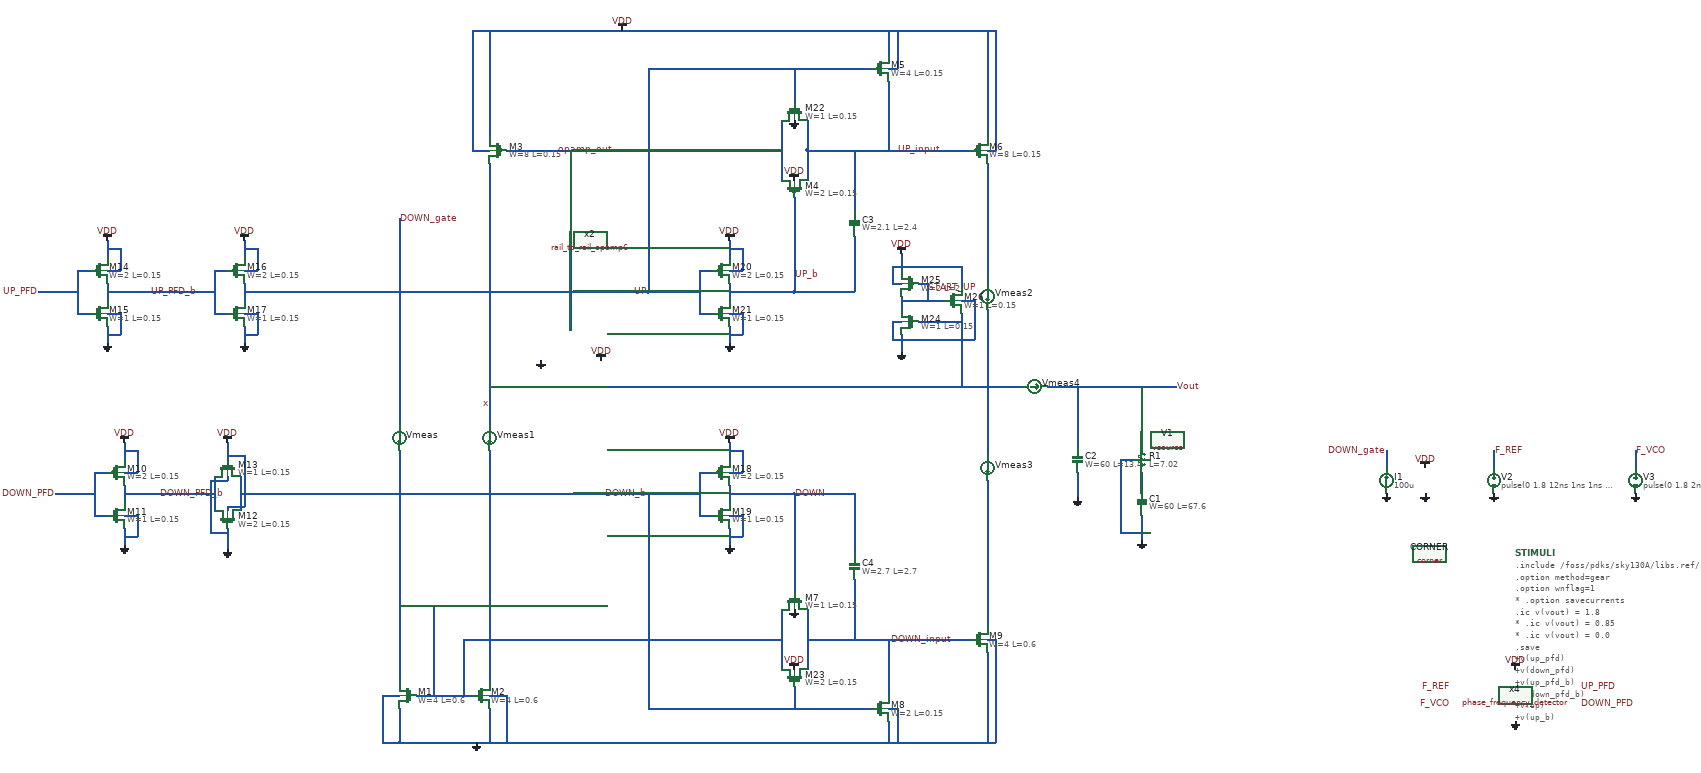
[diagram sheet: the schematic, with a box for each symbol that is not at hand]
v {xschem version=3.4.6 file_version=1.2}
G {}
K {}
V {}
S {}
E {}
B 2 1100 -2730 2140 -2250 {flags=graph
y1=-9.5e-05
y2=0.00017
ypos1=0
ypos2=2
divy=5
subdivy=1
unity=1
x1=-2.5e-08
x2=4.75e-07
divx=5
subdivx=1
xlabmag=1.0
ylabmag=1.0


dataset=0
unitx=1
logx=0
logy=0








linewidth_mult=4
color=6
node="\\"i(@m.xm6.msky130_fd_pr__pfet_01v8[id]) i(@m.xm9.msky130_fd_pr__nfet_01v8[id]) - \\""}
B 2 4200 -3800 5560 -3140 {flags=graph
y1=0
y2=1.8
ypos1=0
ypos2=2
divy=5
subdivy=1
unity=1
x1=-2.5e-08
x2=4.75e-07
divx=5
subdivx=1
xlabmag=1.0
ylabmag=1.0


dataset=0
unitx=1
logx=0
logy=0








linewidth_mult=3







autoload=0
sim_type=tran
color="6 7"
node="f_ref
f_vco"}
B 2 4200 -2410 5580 -1730 {flags=graph
y1=-0.02
y2=1.9
ypos1=0
ypos2=2
divy=5
subdivy=1
unity=1
x1=-2.5e-08
x2=4.75e-07
divx=5
subdivx=1
xlabmag=1.0
ylabmag=1.0


dataset=0
unitx=1
logx=0
logy=0








linewidth_mult=5





color="6 5"
node="up_pfd_b
down_pfd_b"}
B 2 4200 -3120 5580 -2420 {flags=graph
y1=-0.038
y2=1.9
ypos1=0
ypos2=2
divy=5
subdivy=1
unity=1
x1=-2.5e-08
x2=4.75e-07
divx=5
subdivx=1
xlabmag=1.0
ylabmag=1.0


dataset=0
unitx=1
logx=0
logy=0








linewidth_mult=5

color="6 5"
node="up_pfd
down_pfd"}
B 2 2220 -2740 3580 -2070 {flags=graph
y1=0.029
y2=1.9
ypos1=0
ypos2=2
divy=5
subdivy=1
unity=1
x1=-2.5e-08
x2=4.75e-07
divx=5
subdivx=1
xlabmag=1.0
ylabmag=1.0


dataset=0
unitx=1
logx=0
logy=0








linewidth_mult=3



color="9 7 6"
node="vout
x
opamp_out"}
B 2 200 -3250 960 -2910 {flags=graph
y1=-4.8e-06
y2=2
ypos1=0
ypos2=2
divy=5
subdivy=1
unity=1
x1=-2.5e-08
x2=4.75e-07
divx=5
subdivx=1
xlabmag=1.0
ylabmag=1.0


dataset=0
unitx=1
logx=0
logy=0








linewidth_mult=3



color="18 6 11 5 12"
node="opamp_out
up_input


down_gate
down_input


x"}
B 2 1100 -3240 2140 -2750 {flags=graph
y1=-8.2e-05
y2=0.00019
ypos1=0
ypos2=2
divy=5
subdivy=1
unity=1
x1=-2.5e-08
x2=4.75e-07
divx=5
subdivx=1
xlabmag=1.0
ylabmag=1.0


dataset=0
unitx=1
logx=0
logy=0








linewidth_mult=4




color="6 7"
node="i(vmeas2)
i(vmeas3)"}
B 2 2220 -2040 3580 -1370 {flags=graph
y1=0.14
y2=1.9
ypos1=0
ypos2=2
divy=5
subdivy=1
unity=1
x1=-2.5e-08
x2=4.75e-07
divx=5
subdivx=1
xlabmag=1.0
ylabmag=1.0


dataset=0
unitx=1
logx=0
logy=0








linewidth_mult=5



color=6
node=vout}
B 2 4200 -1710 5580 -1030 {flags=graph
y1=-0.013
y2=1.9
ypos1=0
ypos2=2
divy=5
subdivy=1
unity=1
x1=-2.5e-08
x2=4.75e-07
divx=5
subdivx=1
xlabmag=1.0
ylabmag=1.0


dataset=0
unitx=1
logx=0
logy=0








linewidth_mult=5





color="6 5"
node="up
down_b"}
B 2 4200 -1010 5580 -330 {flags=graph
y1=-0.04
y2=1.9
ypos1=0
ypos2=2
divy=5
subdivy=1
unity=1
x1=-2.5e-08
x2=4.75e-07
divx=5
subdivx=1
xlabmag=1.0
ylabmag=1.0


dataset=0
unitx=1
logx=0
logy=0








linewidth_mult=5





color="6 5"
node="up_b
down"}
B 2 40 -2730 1080 -2250 {flags=graph
y1=-9.5e-05
y2=0.00015
ypos1=0
ypos2=2
divy=5
subdivy=1
unity=1
x1=-2.5e-08
x2=4.75e-07
divx=5
subdivx=1
xlabmag=1.0
ylabmag=1.0


dataset=0
unitx=1
logx=0
logy=0








linewidth_mult=2

color="6 7 18"
node="i(vmeas1)
i(vmeas2)
i(vmeas4)"}
N 800 -570 930 -570 {
lab=#net1}
N 760 -540 760 -460 {
lab=GND}
N 760 -460 1260 -460 {
lab=GND}
N 720 -570 760 -570 {
lab=GND}
N 720 -570 720 -460 {
lab=GND}
N 720 -460 760 -460 {
lab=GND}
N 970 -570 1010 -570 {
lab=GND}
N 930 -1840 970 -1840 {
lab=VDD}
N 1260 -460 1300 -460 {
lab=GND}
N 970 -2120 970 -1870 {
lab=VDD}
N 930 -2120 930 -1840 {
lab=VDD}
N 2130 -2120 2130 -1870 {
lab=VDD}
N 1900 -2120 1900 -2060 {
lab=VDD}
N 1900 -2030 1920 -2030 {
lab=VDD}
N 1920 -2120 1920 -2030 {
lab=VDD}
N 2150 -2120 2150 -1840 {
lab=VDD}
N 2130 -1840 2150 -1840 {
lab=VDD}
N 2130 -1810 2130 -1530 {
lab=#net2}
N 1300 -460 1900 -460 {
lab=GND}
N 1900 -510 1900 -460 {
lab=GND}
N 2130 -700 2150 -700 {
lab=GND}
N 2130 -460 2150 -460 {
lab=GND}
N 180 -1510 280 -1510 {
lab=UP_PFD_b}
N 220 -1040 330 -1040 {
lab=DOWN_PFD_b}
N -80 -1510 -40 -1510 {
lab=UP_PFD}
N -40 -1040 0 -1040 {
lab=DOWN_PFD}
N 970 -1810 970 -1410 {
lab=x}
N 970 -1290 1140 -1290 {
lab=x}
N 1180 -1290 2130 -1290 {
lab=#net3}
N 2490 -1090 2490 -1040 {
lab=#net4}
N 2490 -1290 2490 -1150 {
lab=Vout}
N 2490 -990 2490 -930 {
lab=GND}
N 2440 -1120 2470 -1120 {
lab=GND}
N 2440 -1120 2440 -950 {
lab=GND}
N 2440 -950 2490 -950 {
lab=GND}
N 2340 -1290 2340 -1150 {
lab=Vout}
N 2340 -1090 2340 -1030 {
lab=GND}
N 3310 -1140 3310 -1100 {
lab=F_REF}
N 3640 -1140 3640 -1100 {
lab=F_VCO}
N 2270 -1290 2570 -1290 {
lab=Vout}
N 840 -780 840 -570 {
lab=#net1}
N 760 -780 840 -780 {
lab=#net1}
N 1010 -570 1010 -460 {
lab=GND}
N 970 -540 970 -460 {
lab=GND}
N 910 -700 1650 -700 {
lab=#net1}
N 390 -1040 1410 -1040 {
lab=DOWN_b}
N 1680 -1730 1680 -1510 {
lab=UP_b}
N 1340 -2030 1860 -2030 {
lab=UP}
N 1340 -2030 1340 -1510 {
lab=UP}
N 1900 -2000 1900 -1840 {
lab=UP_input}
N 1710 -1840 2090 -1840 {
lab=UP_input}
N 930 -2120 2150 -2120 {
lab=VDD}
N 1620 -1040 1680 -1040 {
lab=DOWN}
N 1680 -1040 1680 -810 {
lab=DOWN}
N 1340 -1040 1340 -540 {
lab=DOWN_b}
N 1340 -540 1860 -540 {
lab=DOWN_b}
N 330 -1080 330 -1000 {
lab=DOWN_PFD_b}
N 390 -1080 390 -1000 {
lab=DOWN_b}
N 360 -1160 360 -1120 {
lab=VDD}
N 360 -1010 360 -1000 {
lab=VDD}
N 360 -1010 400 -1010 {
lab=VDD}
N 400 -1130 400 -1010 {
lab=VDD}
N 360 -1130 400 -1130 {
lab=VDD}
N 360 -1080 360 -1070 {
lab=GND}
N 320 -1070 360 -1070 {
lab=GND}
N 320 -1070 320 -950 {
lab=GND}
N 320 -950 360 -950 {
lab=GND}
N 360 -960 360 -910 {
lab=GND}
N 120 -1060 120 -1020 {
lab=DOWN_PFD_b}
N 50 -1090 80 -1090 {
lab=DOWN_PFD}
N 50 -1090 50 -990 {
lab=DOWN_PFD}
N 50 -990 80 -990 {
lab=DOWN_PFD}
N 120 -1040 220 -1040 {
lab=DOWN_PFD_b}
N 0 -1040 50 -1040 {
lab=DOWN_PFD}
N 120 -960 120 -920 {
lab=GND}
N 120 -1160 120 -1120 {
lab=VDD}
N 120 -1090 150 -1090 {
lab=VDD}
N 150 -1140 150 -1090 {
lab=VDD}
N 120 -1140 150 -1140 {
lab=VDD}
N 120 -990 150 -990 {
lab=GND}
N 150 -990 150 -940 {
lab=GND}
N 120 -940 150 -940 {
lab=GND}
N 80 -1530 80 -1490 {
lab=UP_PFD_b}
N 10 -1560 40 -1560 {
lab=UP_PFD}
N 10 -1560 10 -1460 {
lab=UP_PFD}
N 10 -1460 40 -1460 {
lab=UP_PFD}
N 80 -1510 180 -1510 {
lab=UP_PFD_b}
N -40 -1510 10 -1510 {
lab=UP_PFD}
N 80 -1430 80 -1390 {
lab=GND}
N 80 -1630 80 -1590 {
lab=VDD}
N 80 -1560 110 -1560 {
lab=VDD}
N 110 -1610 110 -1560 {
lab=VDD}
N 80 -1610 110 -1610 {
lab=VDD}
N 80 -1460 110 -1460 {
lab=GND}
N 110 -1460 110 -1410 {
lab=GND}
N 80 -1410 110 -1410 {
lab=GND}
N 400 -1530 400 -1490 {
lab=UP}
N 330 -1560 360 -1560 {
lab=UP_PFD_b}
N 330 -1560 330 -1460 {
lab=UP_PFD_b}
N 330 -1460 360 -1460 {
lab=UP_PFD_b}
N 280 -1510 330 -1510 {
lab=UP_PFD_b}
N 400 -1430 400 -1390 {
lab=GND}
N 400 -1630 400 -1590 {
lab=VDD}
N 400 -1560 430 -1560 {
lab=VDD}
N 430 -1610 430 -1560 {
lab=VDD}
N 400 -1610 430 -1610 {
lab=VDD}
N 400 -1460 430 -1460 {
lab=GND}
N 430 -1460 430 -1410 {
lab=GND}
N 400 -1410 430 -1410 {
lab=GND}
N 1530 -1060 1530 -1020 {
lab=DOWN}
N 1460 -1090 1490 -1090 {
lab=DOWN_b}
N 1460 -1090 1460 -990 {
lab=DOWN_b}
N 1460 -990 1490 -990 {
lab=DOWN_b}
N 1410 -1040 1460 -1040 {
lab=DOWN_b}
N 1530 -960 1530 -920 {
lab=GND}
N 1530 -1160 1530 -1120 {
lab=VDD}
N 1530 -1090 1560 -1090 {
lab=VDD}
N 1560 -1140 1560 -1090 {
lab=VDD}
N 1530 -1140 1560 -1140 {
lab=VDD}
N 1530 -990 1560 -990 {
lab=GND}
N 1560 -990 1560 -940 {
lab=GND}
N 1530 -940 1560 -940 {
lab=GND}
N 1530 -1040 1620 -1040 {
lab=DOWN}
N 1530 -1530 1530 -1490 {
lab=UP_b}
N 1460 -1560 1490 -1560 {
lab=UP}
N 1460 -1560 1460 -1460 {
lab=UP}
N 1460 -1460 1490 -1460 {
lab=UP}
N 1340 -1510 1460 -1510 {
lab=UP}
N 1530 -1430 1530 -1390 {
lab=GND}
N 1530 -1630 1530 -1590 {
lab=VDD}
N 1530 -1560 1560 -1560 {
lab=VDD}
N 1560 -1610 1560 -1560 {
lab=VDD}
N 1530 -1610 1560 -1610 {
lab=VDD}
N 1530 -1460 1560 -1460 {
lab=GND}
N 1560 -1460 1560 -1410 {
lab=GND}
N 1530 -1410 1560 -1410 {
lab=GND}
N 1530 -1510 1620 -1510 {
lab=UP_b}
N 1620 -1510 1680 -1510 {
lab=UP_b}
N 400 -1510 1340 -1510 {
lab=UP}
N 3060 -1140 3060 -1100 {
lab=DOWN_gate}
N 970 -1410 970 -1350 {
lab=x}
N 760 -1680 760 -1200 {
lab=DOWN_gate}
N 970 -1350 970 -1200 {
lab=x}
N 970 -820 970 -600 {
lab=#net5}
N 970 -1140 970 -880 {
lab=#net5}
N 760 -1140 760 -880 {
lab=#net1}
N 760 -820 760 -600 {
lab=#net1}
N 970 -880 970 -820 {
lab=#net5}
N 760 -880 760 -820 {
lab=#net1}
N 1710 -1910 1710 -1840 {
lab=UP_input}
N 1650 -1910 1650 -1770 {
lab=opamp_out}
N 1710 -1840 1710 -1770 {
lab=UP_input}
N 1010 -1840 1650 -1840 {
lab=opamp_out}
N 1900 -460 2130 -460 {
lab=GND}
N 1710 -770 1710 -630 {
lab=DOWN_input}
N 1650 -770 1650 -630 {
lab=#net1}
N 1710 -700 2090 -700 {
lab=DOWN_input}
N 2130 -670 2130 -460 {
lab=GND}
N 2150 -700 2150 -460 {
lab=GND}
N 910 -700 910 -570 {
lab=#net1}
N 1900 -700 1900 -570 {
lab=DOWN_input}
N 1900 -540 1920 -540 {
lab=GND}
N 1920 -540 1920 -460 {
lab=GND}
N 1680 -590 1680 -540 {
lab=DOWN_b}
N 1680 -2030 1680 -1950 {
lab=UP}
N 2130 -1070 2130 -730 {
lab=#net6}
N 2130 -1290 2130 -1130 {
lab=#net3}
N 2130 -1470 2130 -1290 {
lab=#net3}
N 1680 -1510 1820 -1510 {
lab=UP_b}
N 1820 -1640 1820 -1510 {
lab=UP_b}
N 1820 -1840 1820 -1700 {
lab=UP_input}
N 1820 -1040 1820 -900 {
lab=DOWN}
N 1820 -840 1820 -700 {
lab=DOWN_input}
N 1680 -1040 1820 -1040 {
lab=DOWN}
N 2130 -1290 2210 -1290 {
lab=#net3}
N 1160 -1700 1160 -1420 {
lab=opamp_out}
N 1160 -1840 1160 -1760 {
lab=opamp_out}
N 1160 -1760 1160 -1700 {
lab=opamp_out}
N 1930 -1500 1930 -1470 {
lab=START_UP}
N 1910 -1530 1930 -1530 {
lab=VDD}
N 1910 -1570 1910 -1530 {
lab=VDD}
N 1910 -1570 1930 -1570 {
lab=VDD}
N 1910 -1440 1930 -1440 {
lab=GND}
N 1910 -1440 1910 -1400 {
lab=GND}
N 1910 -1400 1930 -1400 {
lab=GND}
N 1930 -1490 2030 -1490 {
lab=START_UP}
N 2070 -1490 2100 -1490 {
lab=GND}
N 2100 -1490 2100 -1400 {
lab=GND}
N 1930 -1400 2100 -1400 {
lab=GND}
N 1970 -1530 1990 -1530 {
lab=START_UP}
N 1990 -1530 1990 -1490 {
lab=START_UP}
N 2070 -1460 2070 -1290 {
lab=#net3}
N 1970 -1440 2070 -1440 {
lab=#net3}
N 1930 -1570 2070 -1570 {
lab=VDD}
N 2070 -1570 2070 -1520 {
lab=VDD}
N 1930 -1410 1930 -1370 {
lab=GND}
N 1930 -1600 1930 -1560 {
lab=VDD}
C {sky130_fd_pr/nfet_01v8.sym} 780 -570 0 1 {name=M1
L=0.6
W=4
nf=1 
mult=1
ad="'int((nf+1)/2) * W/nf * 0.29'" 
pd="'2*int((nf+1)/2) * (W/nf + 0.29)'"
as="'int((nf+2)/2) * W/nf * 0.29'" 
ps="'2*int((nf+2)/2) * (W/nf + 0.29)'"
nrd="'0.29 / W'" nrs="'0.29 / W'"
sa=0 sb=0 sd=0
model=nfet_01v8
spiceprefix=X
}
C {sky130_fd_pr/nfet_01v8.sym} 950 -570 0 0 {name=M2
L=0.6
W=4
nf=1 
mult=1
ad="'int((nf+1)/2) * W/nf * 0.29'" 
pd="'2*int((nf+1)/2) * (W/nf + 0.29)'"
as="'int((nf+2)/2) * W/nf * 0.29'" 
ps="'2*int((nf+2)/2) * (W/nf + 0.29)'"
nrd="'0.29 / W'" nrs="'0.29 / W'"
sa=0 sb=0 sd=0
model=nfet_01v8
spiceprefix=X
}
C {sky130_fd_pr/pfet_01v8.sym} 990 -1840 2 0 {name=M3
L=0.15
W=8
nf=8
mult=1
ad="'int((nf+1)/2) * W/nf * 0.29'" 
pd="'2*int((nf+1)/2) * (W/nf + 0.29)'"
as="'int((nf+2)/2) * W/nf * 0.29'" 
ps="'2*int((nf+2)/2) * (W/nf + 0.29)'"
nrd="'0.29 / W'" nrs="'0.29 / W'"
sa=0 sb=0 sd=0
model=pfet_01v8
spiceprefix=X
}
C {devices/vdd.sym} 1280 -2120 0 0 {name=l13 lab=VDD}
C {devices/gnd.sym} 940 -460 0 0 {name=l14 lab=GND}
C {sky130_fd_pr/corner.sym} 3160 -900 0 0 {name=CORNER only_toplevel=false corner=tt}
C {devices/code.sym} 3360 -901.25 0 0 {name=STIMULI only_toplevel=false value="

.include /foss/pdks/sky130A/libs.ref/sky130_fd_sc_hd/spice/sky130_fd_sc_hd.spice

.option method=gear
.option wnflag=1
* .option savecurrents

.ic v(vout) = 1.8
* .ic v(vout) = 0.85
* .ic v(vout) = 0.0

.save 
+v(up_pfd)
+v(down_pfd)
+v(up_pfd_b)
+v(down_pfd_b)
+v(up)
+v(up_b)
+v(down)
+v(down_b)
+v(v2)
+v(x)
+v(y)
+v(z)
+v(vout)
+v(up_input)
+v(down_input)
+v(down_gate)
+v(opamp_out)
+v(START_UP)
+v(x2.p_bias)
+v(x2.n_bias)
+v(x2.v_common_p)
+v(x2.v_common_n)
+v(x2.p_left)
+v(x2.p_right)
+v(x2.n_left)
+v(x2.n_right)
+v(f_ref)
+v(f_vco)
+v(x4.qa)
+v(x4.qa_b)
+v(x4.qb)
+v(x4.qb_b)
+v(x4.qa)
+v(x4.e)
+v(x4.e_b)
+v(x4.f)
+v(x4.f_b)
+v(x4.before_reset)
+v(x4.reset)
+@m.xm6.msky130_fd_pr__pfet_01v8[id]
+@m.xm9.msky130_fd_pr__nfet_01v8[id]
+@m.xm25.msky130_fd_pr__pfet_01v8[id]
+@m.xm24.msky130_fd_pr__nfet_01v8[id]
+@m.xm26.msky130_fd_pr__nfet_01v8[id]

.control
  * save v(up_pfd) v(down_pfd) v(up_pfd_b) v(down_pfd_b) v(up) v(up_b) v(down) v(down_b) v(x) v(vout) v(up_input) v(down_input)
  * save all

  tran 30ps 0.5us
  remzerovec
  write pfd_charge_pump_12.raw
  set appendwrite

.endc

"}
C {devices/vsource.sym} 3150 -1070 0 0 {name=V1 value=1.8 savecurrent=false}
C {devices/gnd.sym} 3150 -1040 0 0 {name=l2 lab=GND}
C {devices/lab_wire.sym} 970 -1250 0 0 {name=p1 sig_type=std_logic lab=x}
C {devices/vdd.sym} 3150 -1100 0 1 {name=l3 lab=VDD}
C {sky130_fd_pr/pfet_01v8.sym} 1680 -1750 3 0 {name=M4
L=0.15
W=2
nf=2
mult=1
ad="'int((nf+1)/2) * W/nf * 0.29'" 
pd="'2*int((nf+1)/2) * (W/nf + 0.29)'"
as="'int((nf+2)/2) * W/nf * 0.29'" 
ps="'2*int((nf+2)/2) * (W/nf + 0.29)'"
nrd="'0.29 / W'" nrs="'0.29 / W'"
sa=0 sb=0 sd=0
model=pfet_01v8
spiceprefix=X
}
C {sky130_fd_pr/pfet_01v8.sym} 1880 -2030 0 0 {name=M5
L=0.15
W=4
nf=4
mult=1
ad="'int((nf+1)/2) * W/nf * 0.29'" 
pd="'2*int((nf+1)/2) * (W/nf + 0.29)'"
as="'int((nf+2)/2) * W/nf * 0.29'" 
ps="'2*int((nf+2)/2) * (W/nf + 0.29)'"
nrd="'0.29 / W'" nrs="'0.29 / W'"
sa=0 sb=0 sd=0
model=pfet_01v8
spiceprefix=X
}
C {sky130_fd_pr/pfet_01v8.sym} 2110 -1840 0 0 {name=M6
L=0.15
W=8
nf=8
mult=1
ad="'int((nf+1)/2) * W/nf * 0.29'" 
pd="'2*int((nf+1)/2) * (W/nf + 0.29)'"
as="'int((nf+2)/2) * W/nf * 0.29'" 
ps="'2*int((nf+2)/2) * (W/nf + 0.29)'"
nrd="'0.29 / W'" nrs="'0.29 / W'"
sa=0 sb=0 sd=0
model=pfet_01v8
spiceprefix=X
}
C {devices/lab_wire.sym} 1340 -1510 2 1 {name=p4 sig_type=std_logic lab=UP}
C {devices/lab_wire.sym} 1680 -1550 0 1 {name=p5 sig_type=std_logic lab=UP_b}
C {sky130_fd_pr/nfet_01v8.sym} 1680 -790 1 0 {name=M7
L=0.15
W=1
nf=1 
mult=1
ad="'int((nf+1)/2) * W/nf * 0.29'" 
pd="'2*int((nf+1)/2) * (W/nf + 0.29)'"
as="'int((nf+2)/2) * W/nf * 0.29'" 
ps="'2*int((nf+2)/2) * (W/nf + 0.29)'"
nrd="'0.29 / W'" nrs="'0.29 / W'"
sa=0 sb=0 sd=0
model=nfet_01v8
spiceprefix=X
}
C {sky130_fd_pr/nfet_01v8.sym} 1880 -540 0 0 {name=M8
L=0.15
W=2
nf=2 
mult=1
ad="'int((nf+1)/2) * W/nf * 0.29'" 
pd="'2*int((nf+1)/2) * (W/nf + 0.29)'"
as="'int((nf+2)/2) * W/nf * 0.29'" 
ps="'2*int((nf+2)/2) * (W/nf + 0.29)'"
nrd="'0.29 / W'" nrs="'0.29 / W'"
sa=0 sb=0 sd=0
model=nfet_01v8
spiceprefix=X
}
C {devices/lab_wire.sym} 1340 -1040 0 0 {name=p6 sig_type=std_logic lab=DOWN_b}
C {sky130_fd_pr/nfet_01v8.sym} 2110 -700 0 0 {name=M9
L=0.6
W=4
nf=1 
mult=1
ad="'int((nf+1)/2) * W/nf * 0.29'" 
pd="'2*int((nf+1)/2) * (W/nf + 0.29)'"
as="'int((nf+2)/2) * W/nf * 0.29'" 
ps="'2*int((nf+2)/2) * (W/nf + 0.29)'"
nrd="'0.29 / W'" nrs="'0.29 / W'"
sa=0 sb=0 sd=0
model=nfet_01v8
spiceprefix=X
}
C {devices/lab_wire.sym} 180 -1510 0 1 {name=p15 sig_type=std_logic lab=UP_PFD_b}
C {devices/lab_wire.sym} 1920 -1840 2 0 {name=p13 sig_type=std_logic lab=UP_input}
C {devices/lab_wire.sym} 2050 -700 0 0 {name=p14 sig_type=std_logic lab=DOWN_input}
C {devices/gnd.sym} 1090 -1350 0 1 {name=l7 lab=GND}
C {devices/lab_wire.sym} 1260 -1840 0 0 {name=p17 sig_type=std_logic lab=opamp_out}
C {devices/lab_wire.sym} 2570 -1290 0 1 {name=p9 sig_type=std_logic lab=Vout}
C {devices/lab_wire.sym} -80 -1510 0 0 {name=p2 sig_type=std_logic lab=UP_PFD}
C {devices/lab_wire.sym} -40 -1040 2 1 {name=p7 sig_type=std_logic lab=DOWN_PFD}
C {sky130_fd_pr/cap_mim_m3_1.sym} 2340 -1120 0 0 {name=C2 model=cap_mim_m3_1 W=60 L=13.4 MF=1 spiceprefix=X}
C {sky130_fd_pr/cap_mim_m3_1.sym} 2490 -1020 0 0 {name=C1 model=cap_mim_m3_1 W=60 L=67.6 MF=1 spiceprefix=X}
C {devices/gnd.sym} 2490 -930 0 0 {name=l4 lab=GND}
C {devices/gnd.sym} 2340 -1030 0 0 {name=l9 lab=GND
W=60}
C {devices/vsource.sym} 3310 -1070 0 0 {name=V2 value=pulse"(0 1.8 12ns 1ns 1ns 24ns 50ns)" savecurrent=false
* }
C {devices/gnd.sym} 3310 -1040 0 0 {name=l10 lab=GND}
C {devices/lab_pin.sym} 3310 -1140 0 1 {name=p11 sig_type=std_logic lab=F_REF}
C {devices/vsource.sym} 3640 -1070 0 0 {name=V3 value="pulse(0 1.8 2ns 1ns 1ns 24ns 50ns)" savecurrent=false
* "sin(0.9 0.9 20.1MEG)" 1 AC 1}
C {devices/gnd.sym} 3640 -1040 0 0 {name=l15 lab=GND}
C {devices/lab_pin.sym} 3640 -1140 0 1 {name=p12 sig_type=std_logic lab=F_VCO}
C {/foss/designs/my_design/projects/pll/pfd/xschem_ngspice/phase_frequency_detector.sym} 3360 -570 0 0 {name=x4}
C {devices/lab_pin.sym} 3210 -590 0 0 {name=p19 lab=F_REF}
C {devices/lab_pin.sym} 3210 -550 0 0 {name=p20 lab=F_VCO}
C {devices/lab_wire.sym} 3510 -590 0 1 {name=p22 sig_type=std_logic lab=UP_PFD}
C {devices/lab_wire.sym} 3510 -550 2 0 {name=p23 sig_type=std_logic lab=DOWN_PFD}
C {devices/vdd.sym} 3360 -630 0 1 {name=l1 lab=VDD}
C {devices/gnd.sym} 3360 -510 0 0 {name=l8 lab=GND}
C {/foss/designs/my_design/projects/pll/charge_pump/xschem_ngspice/rail_to_rail_opamp6.sym} 1160 -1350 1 1 {name=x2}
C {devices/vdd.sym} 1230 -1350 0 0 {name=l6 lab=VDD}
C {sky130_fd_pr/res_xhigh_po_0p35.sym} 2490 -1120 0 0 {name=R1
L=7.02
model=res_xhigh_po_0p35
spiceprefix=X
mult=1}
C {sky130_fd_pr/pfet_01v8.sym} 360 -980 3 0 {name=M12
L=0.15
W=2
nf=2
mult=1
ad="'int((nf+1)/2) * W/nf * 0.29'" 
pd="'2*int((nf+1)/2) * (W/nf + 0.29)'"
as="'int((nf+2)/2) * W/nf * 0.29'" 
ps="'2*int((nf+2)/2) * (W/nf + 0.29)'"
nrd="'0.29 / W'" nrs="'0.29 / W'"
sa=0 sb=0 sd=0
model=pfet_01v8
spiceprefix=X
}
C {sky130_fd_pr/nfet_01v8.sym} 360 -1100 1 0 {name=M13
L=0.15
W=1
nf=1 
mult=1
ad="'int((nf+1)/2) * W/nf * 0.29'" 
pd="'2*int((nf+1)/2) * (W/nf + 0.29)'"
as="'int((nf+2)/2) * W/nf * 0.29'" 
ps="'2*int((nf+2)/2) * (W/nf + 0.29)'"
nrd="'0.29 / W'" nrs="'0.29 / W'"
sa=0 sb=0 sd=0
model=nfet_01v8
spiceprefix=X
}
C {devices/vdd.sym} 360 -1160 0 0 {name=l11 lab=VDD}
C {devices/gnd.sym} 360 -910 0 0 {name=l12 lab=GND}
C {sky130_fd_pr/pfet_01v8.sym} 100 -1090 0 0 {name=M10
L=0.15
W=2
nf=2
mult=1
ad="'int((nf+1)/2) * W/nf * 0.29'" 
pd="'2*int((nf+1)/2) * (W/nf + 0.29)'"
as="'int((nf+2)/2) * W/nf * 0.29'" 
ps="'2*int((nf+2)/2) * (W/nf + 0.29)'"
nrd="'0.29 / W'" nrs="'0.29 / W'"
sa=0 sb=0 sd=0
model=pfet_01v8
spiceprefix=X
}
C {sky130_fd_pr/nfet_01v8.sym} 100 -990 2 1 {name=M11
L=0.15
W=1
nf=1 
mult=1
ad="'int((nf+1)/2) * W/nf * 0.29'" 
pd="'2*int((nf+1)/2) * (W/nf + 0.29)'"
as="'int((nf+2)/2) * W/nf * 0.29'" 
ps="'2*int((nf+2)/2) * (W/nf + 0.29)'"
nrd="'0.29 / W'" nrs="'0.29 / W'"
sa=0 sb=0 sd=0
model=nfet_01v8
spiceprefix=X
}
C {devices/gnd.sym} 120 -920 0 0 {name=l16 lab=GND}
C {devices/vdd.sym} 120 -1160 0 0 {name=l17 lab=VDD}
C {sky130_fd_pr/pfet_01v8.sym} 60 -1560 0 0 {name=M14
L=0.15
W=2
nf=2
mult=1
ad="'int((nf+1)/2) * W/nf * 0.29'" 
pd="'2*int((nf+1)/2) * (W/nf + 0.29)'"
as="'int((nf+2)/2) * W/nf * 0.29'" 
ps="'2*int((nf+2)/2) * (W/nf + 0.29)'"
nrd="'0.29 / W'" nrs="'0.29 / W'"
sa=0 sb=0 sd=0
model=pfet_01v8
spiceprefix=X
}
C {sky130_fd_pr/nfet_01v8.sym} 60 -1460 2 1 {name=M15
L=0.15
W=1
nf=1 
mult=1
ad="'int((nf+1)/2) * W/nf * 0.29'" 
pd="'2*int((nf+1)/2) * (W/nf + 0.29)'"
as="'int((nf+2)/2) * W/nf * 0.29'" 
ps="'2*int((nf+2)/2) * (W/nf + 0.29)'"
nrd="'0.29 / W'" nrs="'0.29 / W'"
sa=0 sb=0 sd=0
model=nfet_01v8
spiceprefix=X
}
C {devices/gnd.sym} 80 -1390 0 0 {name=l18 lab=GND}
C {devices/vdd.sym} 80 -1630 0 0 {name=l19 lab=VDD}
C {sky130_fd_pr/pfet_01v8.sym} 380 -1560 0 0 {name=M16
L=0.15
W=2
nf=2
mult=1
ad="'int((nf+1)/2) * W/nf * 0.29'" 
pd="'2*int((nf+1)/2) * (W/nf + 0.29)'"
as="'int((nf+2)/2) * W/nf * 0.29'" 
ps="'2*int((nf+2)/2) * (W/nf + 0.29)'"
nrd="'0.29 / W'" nrs="'0.29 / W'"
sa=0 sb=0 sd=0
model=pfet_01v8
spiceprefix=X
}
C {sky130_fd_pr/nfet_01v8.sym} 380 -1460 2 1 {name=M17
L=0.15
W=1
nf=1 
mult=1
ad="'int((nf+1)/2) * W/nf * 0.29'" 
pd="'2*int((nf+1)/2) * (W/nf + 0.29)'"
as="'int((nf+2)/2) * W/nf * 0.29'" 
ps="'2*int((nf+2)/2) * (W/nf + 0.29)'"
nrd="'0.29 / W'" nrs="'0.29 / W'"
sa=0 sb=0 sd=0
model=nfet_01v8
spiceprefix=X
}
C {devices/gnd.sym} 400 -1390 0 0 {name=l20 lab=GND}
C {devices/vdd.sym} 400 -1630 0 0 {name=l21 lab=VDD}
C {sky130_fd_pr/pfet_01v8.sym} 1510 -1090 0 0 {name=M18
L=0.15
W=2
nf=2
mult=1
ad="'int((nf+1)/2) * W/nf * 0.29'" 
pd="'2*int((nf+1)/2) * (W/nf + 0.29)'"
as="'int((nf+2)/2) * W/nf * 0.29'" 
ps="'2*int((nf+2)/2) * (W/nf + 0.29)'"
nrd="'0.29 / W'" nrs="'0.29 / W'"
sa=0 sb=0 sd=0
model=pfet_01v8
spiceprefix=X
}
C {sky130_fd_pr/nfet_01v8.sym} 1510 -990 2 1 {name=M19
L=0.15
W=1
nf=1 
mult=1
ad="'int((nf+1)/2) * W/nf * 0.29'" 
pd="'2*int((nf+1)/2) * (W/nf + 0.29)'"
as="'int((nf+2)/2) * W/nf * 0.29'" 
ps="'2*int((nf+2)/2) * (W/nf + 0.29)'"
nrd="'0.29 / W'" nrs="'0.29 / W'"
sa=0 sb=0 sd=0
model=nfet_01v8
spiceprefix=X
}
C {devices/gnd.sym} 1530 -920 0 0 {name=l22 lab=GND}
C {devices/vdd.sym} 1530 -1160 0 0 {name=l23 lab=VDD}
C {sky130_fd_pr/pfet_01v8.sym} 1510 -1560 0 0 {name=M20
L=0.15
W=2
nf=2
mult=1
ad="'int((nf+1)/2) * W/nf * 0.29'" 
pd="'2*int((nf+1)/2) * (W/nf + 0.29)'"
as="'int((nf+2)/2) * W/nf * 0.29'" 
ps="'2*int((nf+2)/2) * (W/nf + 0.29)'"
nrd="'0.29 / W'" nrs="'0.29 / W'"
sa=0 sb=0 sd=0
model=pfet_01v8
spiceprefix=X
}
C {sky130_fd_pr/nfet_01v8.sym} 1510 -1460 2 1 {name=M21
L=0.15
W=1
nf=1 
mult=1
ad="'int((nf+1)/2) * W/nf * 0.29'" 
pd="'2*int((nf+1)/2) * (W/nf + 0.29)'"
as="'int((nf+2)/2) * W/nf * 0.29'" 
ps="'2*int((nf+2)/2) * (W/nf + 0.29)'"
nrd="'0.29 / W'" nrs="'0.29 / W'"
sa=0 sb=0 sd=0
model=nfet_01v8
spiceprefix=X
}
C {devices/gnd.sym} 1530 -1390 0 0 {name=l24 lab=GND}
C {devices/vdd.sym} 1530 -1630 0 0 {name=l25 lab=VDD}
C {devices/isource.sym} 3060 -1070 2 0 {name=I1 value=100u}
C {devices/gnd.sym} 3060 -1040 0 0 {name=l26 lab=GND}
C {devices/lab_pin.sym} 3060 -1140 2 1 {name=p3 sig_type=std_logic lab=DOWN_gate}
C {devices/lab_wire.sym} 760 -1680 0 1 {name=p16 sig_type=std_logic lab=DOWN_gate}
C {devices/ammeter.sym} 760 -1170 0 0 {name=Vmeas savecurrent=true spice_ignore=0}
C {devices/ammeter.sym} 970 -1170 0 0 {name=Vmeas1 savecurrent=true spice_ignore=0}
C {devices/lab_wire.sym} 200 -1040 2 0 {name=p18 sig_type=std_logic lab=DOWN_PFD_b}
C {devices/lab_wire.sym} 1680 -1040 0 1 {name=p21 sig_type=std_logic lab=DOWN}
C {devices/ammeter.sym} 2130 -1500 0 0 {name=Vmeas2 savecurrent=true spice_ignore=0}
C {devices/ammeter.sym} 2130 -1100 0 0 {name=Vmeas3 savecurrent=true spice_ignore=0}
C {devices/ammeter.sym} 2240 -1290 3 0 {name=Vmeas4 savecurrent=true spice_ignore=0}
C {sky130_fd_pr/nfet_01v8.sym} 1680 -1930 1 0 {name=M22
L=0.15
W=1
nf=1 
mult=1
ad="'int((nf+1)/2) * W/nf * 0.29'" 
pd="'2*int((nf+1)/2) * (W/nf + 0.29)'"
as="'int((nf+2)/2) * W/nf * 0.29'" 
ps="'2*int((nf+2)/2) * (W/nf + 0.29)'"
nrd="'0.29 / W'" nrs="'0.29 / W'"
sa=0 sb=0 sd=0
model=nfet_01v8
spiceprefix=X
}
C {sky130_fd_pr/pfet_01v8.sym} 1680 -610 3 0 {name=M23
L=0.15
W=2
nf=2
mult=1
ad="'int((nf+1)/2) * W/nf * 0.29'" 
pd="'2*int((nf+1)/2) * (W/nf + 0.29)'"
as="'int((nf+2)/2) * W/nf * 0.29'" 
ps="'2*int((nf+2)/2) * (W/nf + 0.29)'"
nrd="'0.29 / W'" nrs="'0.29 / W'"
sa=0 sb=0 sd=0
model=pfet_01v8
spiceprefix=X
}
C {devices/vdd.sym} 1680 -1770 0 0 {name=l5 lab=VDD}
C {devices/gnd.sym} 1680 -1910 0 0 {name=l27 lab=GND}
C {devices/gnd.sym} 1680 -770 0 0 {name=l28 lab=GND}
C {devices/vdd.sym} 1680 -630 0 0 {name=l29 lab=VDD}
C {sky130_fd_pr/cap_mim_m3_1.sym} 1820 -1670 0 0 {name=C3 model=cap_mim_m3_1 W=2.1 L=2.4 MF=1 spiceprefix=X}
C {sky130_fd_pr/cap_mim_m3_1.sym} 1820 -870 0 0 {name=C4 model=cap_mim_m3_1 W=2.7 L=2.7 MF=1 spiceprefix=X}
C {sky130_fd_pr/nfet_01v8.sym} 1950 -1440 0 1 {name=M24
L=0.15
W=1
nf=1 
mult=1
ad="'int((nf+1)/2) * W/nf * 0.29'" 
pd="'2*int((nf+1)/2) * (W/nf + 0.29)'"
as="'int((nf+2)/2) * W/nf * 0.29'" 
ps="'2*int((nf+2)/2) * (W/nf + 0.29)'"
nrd="'0.29 / W'" nrs="'0.29 / W'"
sa=0 sb=0 sd=0
model=nfet_01v8
spiceprefix=X
}
C {sky130_fd_pr/pfet_01v8.sym} 1950 -1530 0 1 {name=M25
L=2
W=2
nf=1
mult=1
ad="'int((nf+1)/2) * W/nf * 0.29'" 
pd="'2*int((nf+1)/2) * (W/nf + 0.29)'"
as="'int((nf+2)/2) * W/nf * 0.29'" 
ps="'2*int((nf+2)/2) * (W/nf + 0.29)'"
nrd="'0.29 / W'" nrs="'0.29 / W'"
sa=0 sb=0 sd=0
model=pfet_01v8
spiceprefix=X
}
C {sky130_fd_pr/nfet_01v8.sym} 2050 -1490 0 0 {name=M26
L=0.15
W=1
nf=1 
mult=1
ad="'int((nf+1)/2) * W/nf * 0.29'" 
pd="'2*int((nf+1)/2) * (W/nf + 0.29)'"
as="'int((nf+2)/2) * W/nf * 0.29'" 
ps="'2*int((nf+2)/2) * (W/nf + 0.29)'"
nrd="'0.29 / W'" nrs="'0.29 / W'"
sa=0 sb=0 sd=0
model=nfet_01v8
spiceprefix=X
}
C {devices/lab_wire.sym} 1990 -1520 0 1 {name=p8 sig_type=std_logic lab=START_UP}
C {devices/gnd.sym} 1930 -1370 0 0 {name=l30 lab=GND}
C {devices/vdd.sym} 1930 -1600 0 0 {name=l31 lab=VDD}
